VERSION 5.7 ;
  NOWIREEXTENSIONATPIN ON ;
  DIVIDERCHAR "/" ;
  BUSBITCHARS "[]" ;
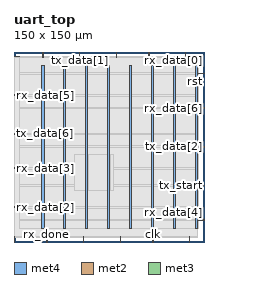
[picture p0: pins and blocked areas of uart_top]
MACRO uart_top
  CLASS BLOCK ;
  FOREIGN uart_top ;
  ORIGIN 0.000 0.000 ;
  SIZE 150.000 BY 150.000 ;
  PIN VGND
    DIRECTION INOUT ;
    USE GROUND ;
    PORT
      LAYER met4 ;
        RECT 39.450 10.640 41.050 138.960 ;
    END
    PORT
      LAYER met4 ;
        RECT 74.180 10.640 75.780 138.960 ;
    END
    PORT
      LAYER met4 ;
        RECT 108.910 10.640 110.510 138.960 ;
    END
    PORT
      LAYER met4 ;
        RECT 143.640 10.640 145.240 138.960 ;
    END
  END VGND
  PIN VPWR
    DIRECTION INOUT ;
    USE POWER ;
    PORT
      LAYER met4 ;
        RECT 22.085 10.640 23.685 138.960 ;
    END
    PORT
      LAYER met4 ;
        RECT 56.815 10.640 58.415 138.960 ;
    END
    PORT
      LAYER met4 ;
        RECT 91.545 10.640 93.145 138.960 ;
    END
    PORT
      LAYER met4 ;
        RECT 126.275 10.640 127.875 138.960 ;
    END
  END VPWR
  PIN clk
    DIRECTION INPUT ;
    USE SIGNAL ;
    ANTENNAGATEAREA 1.286700 ;
    ANTENNADIFFAREA 0.434700 ;
    PORT
      LAYER met2 ;
        RECT 109.570 0.000 109.850 4.000 ;
    END
  END clk
  PIN rst
    DIRECTION INPUT ;
    USE SIGNAL ;
    ANTENNAGATEAREA 0.631200 ;
    ANTENNADIFFAREA 0.434700 ;
    PORT
      LAYER met3 ;
        RECT 146.000 132.640 150.000 133.240 ;
    END
  END rst
  PIN rx_data[0]
    DIRECTION OUTPUT TRISTATE ;
    USE SIGNAL ;
    ANTENNADIFFAREA 0.795200 ;
    PORT
      LAYER met2 ;
        RECT 135.330 146.000 135.610 150.000 ;
    END
  END rx_data[0]
  PIN rx_data[1]
    DIRECTION OUTPUT TRISTATE ;
    USE SIGNAL ;
    ANTENNADIFFAREA 0.795200 ;
    PORT
      LAYER met2 ;
        RECT 80.590 146.000 80.870 150.000 ;
    END
  END rx_data[1]
  PIN rx_data[2]
    DIRECTION OUTPUT TRISTATE ;
    USE SIGNAL ;
    ANTENNADIFFAREA 0.795200 ;
    PORT
      LAYER met3 ;
        RECT 0.000 27.240 4.000 27.840 ;
    END
  END rx_data[2]
  PIN rx_data[3]
    DIRECTION OUTPUT TRISTATE ;
    USE SIGNAL ;
    ANTENNADIFFAREA 0.795200 ;
    PORT
      LAYER met3 ;
        RECT 0.000 57.840 4.000 58.440 ;
    END
  END rx_data[3]
  PIN rx_data[4]
    DIRECTION OUTPUT TRISTATE ;
    USE SIGNAL ;
    ANTENNADIFFAREA 0.445500 ;
    PORT
      LAYER met3 ;
        RECT 146.000 17.040 150.000 17.640 ;
    END
  END rx_data[4]
  PIN rx_data[5]
    DIRECTION OUTPUT TRISTATE ;
    USE SIGNAL ;
    ANTENNADIFFAREA 0.795200 ;
    PORT
      LAYER met3 ;
        RECT 0.000 115.640 4.000 116.240 ;
    END
  END rx_data[5]
  PIN rx_data[6]
    DIRECTION OUTPUT TRISTATE ;
    USE SIGNAL ;
    ANTENNADIFFAREA 0.445500 ;
    PORT
      LAYER met3 ;
        RECT 146.000 105.440 150.000 106.040 ;
    END
  END rx_data[6]
  PIN rx_data[7]
    DIRECTION OUTPUT TRISTATE ;
    USE SIGNAL ;
    ANTENNADIFFAREA 0.795200 ;
    PORT
      LAYER met2 ;
        RECT 0.090 0.000 0.370 4.000 ;
    END
  END rx_data[7]
  PIN rx_done
    DIRECTION OUTPUT TRISTATE ;
    USE SIGNAL ;
    ANTENNADIFFAREA 0.795200 ;
    PORT
      LAYER met2 ;
        RECT 25.850 0.000 26.130 4.000 ;
    END
  END rx_done
  PIN tx_busy
    DIRECTION OUTPUT TRISTATE ;
    USE SIGNAL ;
    ANTENNADIFFAREA 0.795200 ;
    PORT
      LAYER met2 ;
        RECT 138.550 0.000 138.830 4.000 ;
    END
  END tx_busy
  PIN tx_data[0]
    DIRECTION INPUT ;
    USE SIGNAL ;
    ANTENNAGATEAREA 0.631200 ;
    ANTENNADIFFAREA 0.434700 ;
    PORT
      LAYER met2 ;
        RECT 54.830 0.000 55.110 4.000 ;
    END
  END tx_data[0]
  PIN tx_data[1]
    DIRECTION INPUT ;
    USE SIGNAL ;
    ANTENNAGATEAREA 0.631200 ;
    ANTENNADIFFAREA 0.434700 ;
    PORT
      LAYER met2 ;
        RECT 51.610 146.000 51.890 150.000 ;
    END
  END tx_data[1]
  PIN tx_data[2]
    DIRECTION INPUT ;
    USE SIGNAL ;
    ANTENNAGATEAREA 0.631200 ;
    ANTENNADIFFAREA 0.434700 ;
    PORT
      LAYER met3 ;
        RECT 146.000 74.840 150.000 75.440 ;
    END
  END tx_data[2]
  PIN tx_data[3]
    DIRECTION INPUT ;
    USE SIGNAL ;
    ANTENNAGATEAREA 0.631200 ;
    ANTENNADIFFAREA 0.434700 ;
    PORT
      LAYER met3 ;
        RECT 0.000 146.240 4.000 146.840 ;
    END
  END tx_data[3]
  PIN tx_data[4]
    DIRECTION INPUT ;
    USE SIGNAL ;
    ANTENNAGATEAREA 0.631200 ;
    ANTENNADIFFAREA 0.434700 ;
    PORT
      LAYER met2 ;
        RECT 106.350 146.000 106.630 150.000 ;
    END
  END tx_data[4]
  PIN tx_data[5]
    DIRECTION INPUT ;
    USE SIGNAL ;
    ANTENNAGATEAREA 0.631200 ;
    ANTENNADIFFAREA 0.434700 ;
    PORT
      LAYER met2 ;
        RECT 83.810 0.000 84.090 4.000 ;
    END
  END tx_data[5]
  PIN tx_data[6]
    DIRECTION INPUT ;
    USE SIGNAL ;
    ANTENNAGATEAREA 0.631200 ;
    ANTENNADIFFAREA 0.434700 ;
    PORT
      LAYER met3 ;
        RECT 0.000 85.040 4.000 85.640 ;
    END
  END tx_data[6]
  PIN tx_data[7]
    DIRECTION INPUT ;
    USE SIGNAL ;
    ANTENNAGATEAREA 0.631200 ;
    ANTENNADIFFAREA 0.434700 ;
    PORT
      LAYER met2 ;
        RECT 22.630 146.000 22.910 150.000 ;
    END
  END tx_data[7]
  PIN tx_start
    DIRECTION INPUT ;
    USE SIGNAL ;
    ANTENNAGATEAREA 0.647700 ;
    ANTENNADIFFAREA 0.434700 ;
    PORT
      LAYER met3 ;
        RECT 146.000 44.240 150.000 44.840 ;
    END
  END tx_start
  OBS
      LAYER li1 ;
        RECT 5.520 10.795 144.440 138.805 ;
      LAYER met1 ;
        RECT 0.070 10.640 145.240 138.960 ;
      LAYER met2 ;
        RECT 0.100 145.720 22.350 146.725 ;
        RECT 23.190 145.720 51.330 146.725 ;
        RECT 52.170 145.720 80.310 146.725 ;
        RECT 81.150 145.720 106.070 146.725 ;
        RECT 106.910 145.720 135.050 146.725 ;
        RECT 135.890 145.720 145.210 146.725 ;
        RECT 0.100 4.280 145.210 145.720 ;
        RECT 0.650 3.670 25.570 4.280 ;
        RECT 26.410 3.670 54.550 4.280 ;
        RECT 55.390 3.670 83.530 4.280 ;
        RECT 84.370 3.670 109.290 4.280 ;
        RECT 110.130 3.670 138.270 4.280 ;
        RECT 139.110 3.670 145.210 4.280 ;
      LAYER met3 ;
        RECT 4.400 145.840 146.000 146.705 ;
        RECT 3.990 133.640 146.000 145.840 ;
        RECT 3.990 132.240 145.600 133.640 ;
        RECT 3.990 116.640 146.000 132.240 ;
        RECT 4.400 115.240 146.000 116.640 ;
        RECT 3.990 106.440 146.000 115.240 ;
        RECT 3.990 105.040 145.600 106.440 ;
        RECT 3.990 86.040 146.000 105.040 ;
        RECT 4.400 84.640 146.000 86.040 ;
        RECT 3.990 75.840 146.000 84.640 ;
        RECT 3.990 74.440 145.600 75.840 ;
        RECT 3.990 58.840 146.000 74.440 ;
        RECT 4.400 57.440 146.000 58.840 ;
        RECT 3.990 45.240 146.000 57.440 ;
        RECT 3.990 43.840 145.600 45.240 ;
        RECT 3.990 28.240 146.000 43.840 ;
        RECT 4.400 26.840 146.000 28.240 ;
        RECT 3.990 18.040 146.000 26.840 ;
        RECT 3.990 16.640 145.600 18.040 ;
        RECT 3.990 10.715 146.000 16.640 ;
      LAYER met4 ;
        RECT 48.135 40.975 56.415 69.185 ;
        RECT 58.815 40.975 73.780 69.185 ;
        RECT 76.180 40.975 78.825 69.185 ;
  END
END uart_top
END LIBRARY

